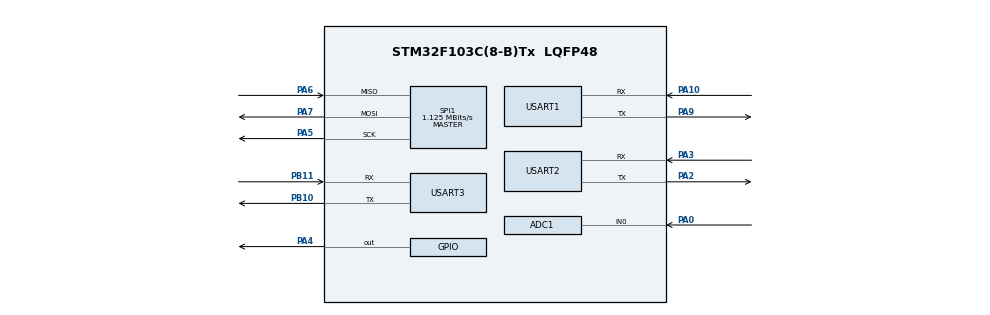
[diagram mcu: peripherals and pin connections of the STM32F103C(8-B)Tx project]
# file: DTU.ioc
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ADC1.Channel-0\#ChannelRegularConversion=ADC_CHANNEL_0
ADC1.NbrOfConversionFlag=1
ADC1.Rank-0\#ChannelRegularConversion=1
ADC1.SamplingTime-0\#ChannelRegularConversion=ADC_SAMPLETIME_1CYCLE_5
ADC1.master=1
Mcu.Family=STM32F1
Mcu.Name=STM32F103C(8-B)Tx
Mcu.Package=LQFP48
NVIC.PriorityGroup=NVIC_PRIORITYGROUP_4
NVIC.USART1_IRQn=true\:0\:0\:false\:false\:true
NVIC.USART2_IRQn=true\:0\:0\:false\:false\:true
NVIC.USART3_IRQn=true\:0\:0\:false\:false\:true
PA0-WKUP.Signal=ADCx_IN0
PA10.Mode=Asynchronous
PA10.Signal=USART1_RX
PA13.Mode=Serial_Wire
PA13.Signal=SYS_JTMS-SWDIO
PA14.Mode=Serial_Wire
PA14.Signal=SYS_JTCK-SWCLK
PA2.Mode=Asynchronous
PA2.Signal=USART2_TX
PA3.Mode=Asynchronous
PA3.Signal=USART2_RX
PA4.Signal=GPIO_Output
PA5.Mode=Full_Duplex_Master
PA5.Signal=SPI1_SCK
PA6.Mode=Full_Duplex_Master
PA6.Signal=SPI1_MISO
PA7.Mode=Full_Duplex_Master
PA7.Signal=SPI1_MOSI
PA9.Mode=Asynchronous
PA9.Signal=USART1_TX
PB10.Mode=Asynchronous
PB10.Signal=USART3_TX
PB11.Mode=Asynchronous
PB11.Signal=USART3_RX
PD0-OSC_IN.Mode=HSE-External-Oscillator
PD0-OSC_IN.Signal=RCC_OSC_IN
PD1-OSC_OUT.Mode=HSE-External-Oscillator
PD1-OSC_OUT.Signal=RCC_OSC_OUT
ProjectManager.HeapSize=0x200
ProjectManager.StackSize=0x400
ProjectManager.TargetToolchain=MDK-ARM V5
RCC.ADCPresc=RCC_ADCPCLK2_DIV6
RCC.AHBFreq_Value=72000000
RCC.APB1CLKDivider=RCC_HCLK_DIV2
RCC.APB1Freq_Value=36000000
RCC.APB1TimFreq_Value=72000000
RCC.APB2Freq_Value=72000000
RCC.APB2TimFreq_Value=72000000
RCC.HCLKFreq_Value=72000000
RCC.HSIState=RCC_HSI_ON
RCC.PLLMUL=RCC_PLL_MUL9
RCC.PLLSourceVirtual=RCC_PLLSOURCE_HSE
RCC.SYSCLKFreq_VALUE=72000000
RCC.SYSCLKSource=RCC_SYSCLKSOURCE_PLLCLK
RCC.USBFreq_Value=72000000
SH.ADCx_IN0.0=ADC1_IN0,IN0
SPI1.BaudRatePrescaler=SPI_BAUDRATEPRESCALER_64
SPI1.CalculateBaudRate=1.125 MBits/s
SPI1.Mode=SPI_MODE_MASTER
board=DTU

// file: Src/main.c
/**
  ******************************************************************************
  * File Name          : main.c
  * Description        : Main program body
  ******************************************************************************
  *
  * COPYRIGHT(c) 2016 STMicroelectronics
  *
  * Redistribution and use in source and binary forms, with or without modification,
  * are permitted provided that the following conditions are met:
  *   1. Redistributions of source code must retain the above copyright notice,
  *      this list of conditions and the following disclaimer.
  *   2. Redistributions in binary form must reproduce the above copyright notice,
  *      this list of conditions and the following disclaimer in the documentation
  *      and/or other materials provided with the distribution.
  *   3. Neither the name of STMicroelectronics nor the names of its contributors
  *      may be used to endorse or promote products derived from this software
  *      without specific prior written permission.
  *
  * THIS SOFTWARE IS PROVIDED BY THE COPYRIGHT HOLDERS AND CONTRIBUTORS "AS IS"
  * AND ANY EXPRESS OR IMPLIED WARRANTIES, INCLUDING, BUT NOT LIMITED TO, THE
  * IMPLIED WARRANTIES OF MERCHANTABILITY AND FITNESS FOR A PARTICULAR PURPOSE ARE
  * DISCLAIMED. IN NO EVENT SHALL THE COPYRIGHT HOLDER OR CONTRIBUTORS BE LIABLE
  * FOR ANY DIRECT, INDIRECT, INCIDENTAL, SPECIAL, EXEMPLARY, OR CONSEQUENTIAL
  * DAMAGES (INCLUDING, BUT NOT LIMITED TO, PROCUREMENT OF SUBSTITUTE GOODS OR
  * SERVICES; LOSS OF USE, DATA, OR PROFITS; OR BUSINESS INTERRUPTION) HOWEVER
  * CAUSED AND ON ANY THEORY OF LIABILITY, WHETHER IN CONTRACT, STRICT LIABILITY,
  * OR TORT (INCLUDING NEGLIGENCE OR OTHERWISE) ARISING IN ANY WAY OUT OF THE USE
  * OF THIS SOFTWARE, EVEN IF ADVISED OF THE POSSIBILITY OF SUCH DAMAGE.
  *
  ******************************************************************************
  */
#include "stm32f1xx_hal.h"
#include "Drv_EC20.h"
#include "UserMain.h"
#include "FLASH_MX25.h"

ADC_HandleTypeDef hadc1;

SPI_HandleTypeDef hspi1;

UART_HandleTypeDef huart1;
UART_HandleTypeDef huart2;
UART_HandleTypeDef huart3;

/* USER CODE BEGIN PV */
/* Private variables ---------------------------------------------------------*/

/* USER CODE END PV */

void SystemClock_Config(void);
void Error_Handler(void);
static void MX_GPIO_Init(void);
static void MX_ADC1_Init(void);
static void MX_SPI1_Init(void);
static void MX_USART1_UART_Init(void);
static void MX_USART2_UART_Init(void);
static void MX_USART3_UART_Init(void);

/* USER CODE BEGIN PFP */
/* Private function prototypes -----------------------------------------------*/

/* USER CODE END PFP */

/* USER CODE BEGIN 0 */
extern void UserInit(void);
extern void UserMain(void);
extern void EC20PowON(void);
/* USER CODE END 0 */
int main(void)
{
  /* MCU Configuration----------------------------------------------------------*/
  /* Reset of all peripherals, Initializes the Flash interface and the Systick. */
  HAL_Init();
  /* Configure the system clock */
  SystemClock_Config();
  /* Initialize all configured peripherals */
  MX_GPIO_Init();
  MX_ADC1_Init();
  MX_SPI1_Init();
  MX_USART1_UART_Init();
  MX_USART2_UART_Init();
  MX_USART3_UART_Init();
//FLASH_Test();
  /* USER CODE BEGIN 2 */
    UserInit();
    EC20PowON();
  /* USER CODE END 2 */
  /* Infinite loop */
  /* USER CODE BEGIN WHILE */

  // 实测50ms：Flash、GPRS模块等都要求上电在电源稳定后延时等待
  // 期间只有UserMain()需要的时间标识会在中断里面置位、这个无副作用
  FlashDelayMs(3);
  DebugOutStr("\r\n\r\nsys start.\r\n",sizeof("\r\n\r\nsys start.\r\n") - 1);
  Print_DTU_Version();
  while (1)
  {
      UserMain();
  /* USER CODE END WHILE */
  }
}

/** System Clock Configuration
*/
void SystemClock_Config(void)
{

  RCC_OscInitTypeDef RCC_OscInitStruct;
  RCC_ClkInitTypeDef RCC_ClkInitStruct;
  RCC_PeriphCLKInitTypeDef PeriphClkInit;

  RCC_OscInitStruct.OscillatorType = RCC_OSCILLATORTYPE_HSI;
  RCC_OscInitStruct.HSIState = RCC_HSI_ON;
  RCC_OscInitStruct.HSICalibrationValue = RCC_HSICALIBRATION_DEFAULT;
  RCC_OscInitStruct.PLL.PLLState = RCC_PLL_ON;
  RCC_OscInitStruct.PLL.PLLSource = RCC_PLLSOURCE_HSI_DIV2;
  RCC_OscInitStruct.PLL.PLLMUL = RCC_PLL_MUL9;
  if (HAL_RCC_OscConfig(&RCC_OscInitStruct) != HAL_OK)
  {
    Error_Handler();
  }

  RCC_ClkInitStruct.ClockType = RCC_CLOCKTYPE_HCLK|RCC_CLOCKTYPE_SYSCLK
                              |RCC_CLOCKTYPE_PCLK1|RCC_CLOCKTYPE_PCLK2;
  RCC_ClkInitStruct.SYSCLKSource = RCC_SYSCLKSOURCE_PLLCLK;
  RCC_ClkInitStruct.AHBCLKDivider = RCC_SYSCLK_DIV1;
  RCC_ClkInitStruct.APB1CLKDivider = RCC_HCLK_DIV2;
  RCC_ClkInitStruct.APB2CLKDivider = RCC_HCLK_DIV1;
  if (HAL_RCC_ClockConfig(&RCC_ClkInitStruct, FLASH_LATENCY_2) != HAL_OK)
  {
    Error_Handler();
  }

  PeriphClkInit.PeriphClockSelection = RCC_PERIPHCLK_ADC;
  PeriphClkInit.AdcClockSelection = RCC_ADCPCLK2_DIV6;
  if (HAL_RCCEx_PeriphCLKConfig(&PeriphClkInit) != HAL_OK)
  {
    Error_Handler();
  }

  HAL_SYSTICK_Config(HAL_RCC_GetHCLKFreq()/1000);

  HAL_SYSTICK_CLKSourceConfig(SYSTICK_CLKSOURCE_HCLK);

  /* SysTick_IRQn interrupt configuration */
  HAL_NVIC_SetPriority(SysTick_IRQn, 0, 0);
}

/* ADC1 init function */
static void MX_ADC1_Init(void)
{

  ADC_ChannelConfTypeDef sConfig;

    /**Common config
    */
  hadc1.Instance = ADC1;
  hadc1.Init.ScanConvMode = ADC_SCAN_DISABLE;
  hadc1.Init.ContinuousConvMode = DISABLE;
  hadc1.Init.DiscontinuousConvMode = DISABLE;
  hadc1.Init.ExternalTrigConv = ADC_SOFTWARE_START;
  hadc1.Init.DataAlign = ADC_DATAALIGN_RIGHT;
  hadc1.Init.NbrOfConversion = 1;
  if (HAL_ADC_Init(&hadc1) != HAL_OK)
  {
    Error_Handler();
  }

    /**Configure Regular Channel
    */
  sConfig.Channel = ADC_CHANNEL_0;
  sConfig.Rank = 1;
  sConfig.SamplingTime = ADC_SAMPLETIME_1CYCLE_5;
  if (HAL_ADC_ConfigChannel(&hadc1, &sConfig) != HAL_OK)
  {
    Error_Handler();
  }

}

/* SPI1 init function */
static void MX_SPI1_Init(void)
{

  hspi1.Instance = SPI1;
  hspi1.Init.Mode = SPI_MODE_MASTER;
  hspi1.Init.Direction = SPI_DIRECTION_2LINES;
  hspi1.Init.DataSize = SPI_DATASIZE_8BIT;
  hspi1.Init.CLKPolarity = SPI_POLARITY_LOW;
  hspi1.Init.CLKPhase = SPI_PHASE_1EDGE;
  hspi1.Init.NSS = SPI_NSS_SOFT;
  hspi1.Init.BaudRatePrescaler = SPI_BAUDRATEPRESCALER_64;
  hspi1.Init.FirstBit = SPI_FIRSTBIT_MSB;
  hspi1.Init.TIMode = SPI_TIMODE_DISABLE;
  hspi1.Init.CRCCalculation = SPI_CRCCALCULATION_DISABLE;
  hspi1.Init.CRCPolynomial = 10;
  if (HAL_SPI_Init(&hspi1) != HAL_OK)
  {
    Error_Handler();
  }

}

/* USART1 init function */
/* 与主控板进行通信 */
static void MX_USART1_UART_Init(void)
{

  huart1.Instance = USART1;
  huart1.Init.BaudRate = 57600;
  huart1.Init.WordLength = UART_WORDLENGTH_8B;
  huart1.Init.StopBits = UART_STOPBITS_1;
  huart1.Init.Parity = UART_PARITY_NONE;
  huart1.Init.Mode = UART_MODE_TX_RX;
  huart1.Init.HwFlowCtl = UART_HWCONTROL_NONE;
  huart1.Init.OverSampling = UART_OVERSAMPLING_16;
  if (HAL_UART_Init(&huart1) != HAL_OK)
  {
    Error_Handler();
  }

}

/* USART2 init function */
/* 打印调试信息 */
static void MX_USART2_UART_Init(void)
{

  huart2.Instance = USART2;
  huart2.Init.BaudRate = 115200;
  huart2.Init.WordLength = UART_WORDLENGTH_8B;
  huart2.Init.StopBits = UART_STOPBITS_1;
  huart2.Init.Parity = UART_PARITY_NONE;
  huart2.Init.Mode = UART_MODE_TX_RX;
  huart2.Init.HwFlowCtl = UART_HWCONTROL_NONE;
  huart2.Init.OverSampling = UART_OVERSAMPLING_16;
  if (HAL_UART_Init(&huart2) != HAL_OK)
  {
    Error_Handler();
  }

}

/* USART3 init function */
/* 与GPRS模块进行通信 */
static void MX_USART3_UART_Init(void)
{

  huart3.Instance = USART3;
  huart3.Init.BaudRate = 115200;
  huart3.Init.WordLength = UART_WORDLENGTH_8B;
  huart3.Init.StopBits = UART_STOPBITS_1;
  huart3.Init.Parity = UART_PARITY_NONE;
  huart3.Init.Mode = UART_MODE_TX_RX;
  huart3.Init.HwFlowCtl = UART_HWCONTROL_NONE;
  huart3.Init.OverSampling = UART_OVERSAMPLING_16;
  if (HAL_UART_Init(&huart3) != HAL_OK)
  {
    Error_Handler();
  }

}

/** Configure pins as
        * Analog
        * Input
        * Output
        * EVENT_OUT
        * EXTI
        * Free pins are configured automatically as Analog (this feature is enabled through
        * the Code Generation settings)
*/
static void MX_GPIO_Init(void)
{

  GPIO_InitTypeDef GPIO_InitStruct;

  /* GPIO Ports Clock Enable */
  __HAL_RCC_GPIOC_CLK_ENABLE();
  __HAL_RCC_GPIOD_CLK_ENABLE();
  __HAL_RCC_GPIOA_CLK_ENABLE();
  __HAL_RCC_GPIOB_CLK_ENABLE();

  /*Configure GPIO pins : PC13 PC14 PC15 */
  GPIO_InitStruct.Pin = GPIO_PIN_13|GPIO_PIN_14|GPIO_PIN_15;
  GPIO_InitStruct.Mode = GPIO_MODE_ANALOG;
  HAL_GPIO_Init(GPIOC, &GPIO_InitStruct);

  /*Configure GPIO pins : PA1 PA8 PA11 PA12
                           PA15 */
  GPIO_InitStruct.Pin = GPIO_PIN_1|GPIO_PIN_8|GPIO_PIN_11|GPIO_PIN_12
                          |GPIO_PIN_15;
  GPIO_InitStruct.Mode = GPIO_MODE_ANALOG;
  HAL_GPIO_Init(GPIOA, &GPIO_InitStruct);

  /*Configure GPIO pin : PA4 */
  GPIO_InitStruct.Pin = GPIO_PIN_4;
  GPIO_InitStruct.Mode = GPIO_MODE_OUTPUT_PP;
  GPIO_InitStruct.Speed = GPIO_SPEED_FREQ_LOW;
  HAL_GPIO_Init(GPIOA, &GPIO_InitStruct);

  /*Configure GPIO pins : PB0 PB1 PB2 PB12
                           PB13 PB14 PB15 PB3
                           PB4 PB5 PB6 PB7
                           PB8 PB9 */
  GPIO_InitStruct.Pin = GPIO_PIN_0|GPIO_PIN_1|GPIO_PIN_2|GPIO_PIN_12
                          |GPIO_PIN_13|GPIO_PIN_14|GPIO_PIN_15|GPIO_PIN_3
                          |GPIO_PIN_4|GPIO_PIN_5|GPIO_PIN_6|GPIO_PIN_7
                          |GPIO_PIN_8|GPIO_PIN_9|GPIO_PIN_12;
  GPIO_InitStruct.Mode = GPIO_MODE_ANALOG;
  HAL_GPIO_Init(GPIOB, &GPIO_InitStruct);

  /*Configure GPIO pin Output Level */
  //HAL_GPIO_WritePin(GPIOA, GPIO_PIN_4, GPIO_PIN_RESET);

    GPIO_InitStruct.Pin = IO_GSM_PWR_PIN;
    GPIO_InitStruct.Mode = GPIO_MODE_OUTPUT_PP;
    GPIO_InitStruct.Speed = GPIO_SPEED_FREQ_HIGH;
    HAL_GPIO_Init(IO_GSM_PWR_GPIO, &GPIO_InitStruct);
    HAL_GPIO_WritePin(IO_GSM_PWR_GPIO, IO_GSM_PWR_PIN, GPIO_PIN_SET);

    GPIO_InitStruct.Pin = IO_FLASH_CS_PIN;
    GPIO_InitStruct.Mode = GPIO_MODE_OUTPUT_PP;
    GPIO_InitStruct.Speed = GPIO_SPEED_FREQ_HIGH;
    HAL_GPIO_Init(IO_FLASH_CS_GPIO, &GPIO_InitStruct);
    HAL_GPIO_WritePin(IO_FLASH_CS_GPIO, IO_FLASH_CS_PIN, GPIO_PIN_SET);

    GPIO_InitStruct.Pin = IO_FLASH_HOLD_PIN;
    GPIO_InitStruct.Mode = GPIO_MODE_OUTPUT_PP;
    GPIO_InitStruct.Speed = GPIO_SPEED_FREQ_HIGH;
    HAL_GPIO_Init(IO_FLASH_HOLD_GPIO, &GPIO_InitStruct);
    HAL_GPIO_WritePin(IO_FLASH_HOLD_GPIO, IO_FLASH_HOLD_PIN, GPIO_PIN_SET);
}

void Error_Handler(void)
{
  while(1)
  {
  }
}

/************************ (C) COPYRIGHT STMicroelectronics *****END OF FILE****/
